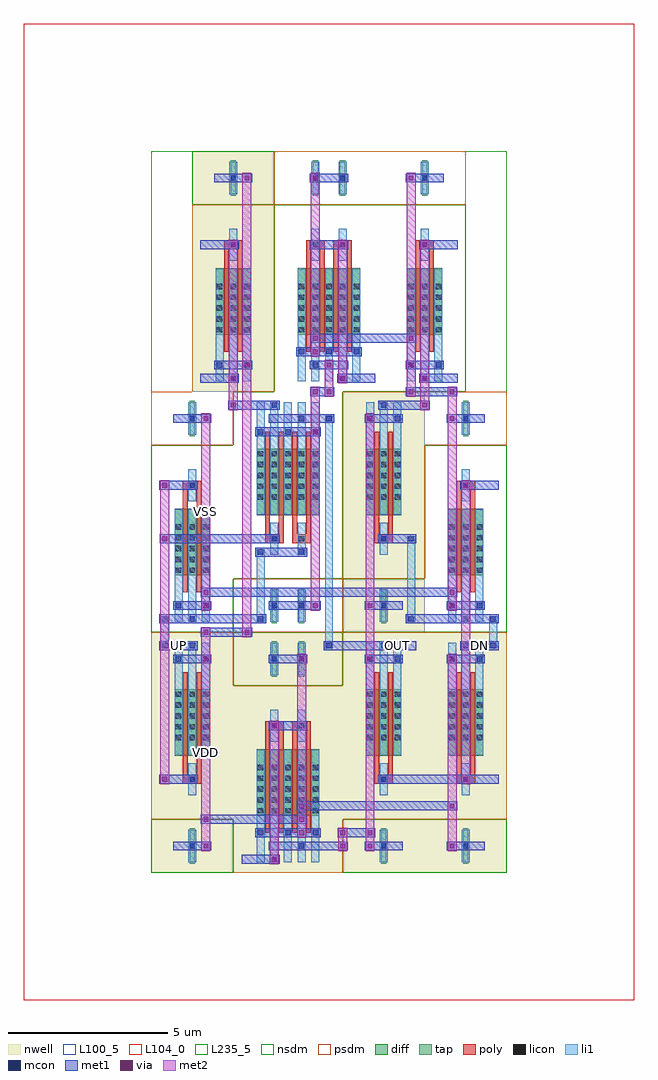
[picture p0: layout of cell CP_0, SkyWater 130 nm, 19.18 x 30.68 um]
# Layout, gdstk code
from math import pi, radians
import gdstk
lib = gdstk.Library(unit=1e-6, precision=1e-09)
def R(c, l, rs):  # rectangles x0, y0, x1, y1
    for r in rs: c.add(gdstk.rectangle(r[:2], r[2:], *l))
def A(c, l, x, y, w, h, nx, ny, dx, dy):  # array of equal rectangles
    R(c, l, [(x+i*dx, y+j*dy, x+i*dx+w, y+j*dy+h) for i in range(nx) for j in range(ny)])
def P(c, l, *ps):  # polygons
    for p in ps: c.add(gdstk.Polygon(p, *l))
nwell = (64, 20)
diff = (65, 20)
tap = (65, 44)
poly = (66, 20)
licon = (66, 44)
li1 = (67, 20)
mcon = (67, 44)
met1 = (68, 20)
via = (68, 44)
met2 = (69, 20)
nsdm = (93, 44)
psdm = (94, 20)
L100_5 = (100, 5)
L104_0 = (104, 0)
L235_5 = (235, 5)

scm_nmos_4295876_x1_y1_1 = lib.new_cell('SCM_NMOS_4295876_X1_Y1_1676481576')
R(scm_nmos_4295876_x1_y1_1, diff, [(0.735,1.785,2.705,3.885)])
R(scm_nmos_4295876_x1_y1_1, tap, [(1.205,6.16,1.375,7.28), (2.065,6.16,2.235,7.28)])
A(scm_nmos_4295876_x1_y1_1, poly, 1, 1.26, 0.15, 3.36, 4, 1, 0.43, 0)
R(scm_nmos_4295876_x1_y1_1, poly, [(1,4.485,1.58,4.755), (1.86,4.485,2.44,4.755)])
A(scm_nmos_4295876_x1_y1_1, licon, 0.775, 1.865, 0.17, 0.17, 3, 5, 0.43, 0.34)
A(scm_nmos_4295876_x1_y1_1, licon, 1.635, 1.865, 0.17, 0.17, 3, 5, 0.43, 0.34)
R(scm_nmos_4295876_x1_y1_1, licon, [(1.205,4.535,1.375,4.705), (2.065,4.535,2.235,4.705), (1.205,6.635,1.375,6.805), (2.065,6.635,2.235,6.805)])
A(scm_nmos_4295876_x1_y1_1, li1, 0.735, 0.335, 0.25, 3.53, 5, 1, 0.43, 0)
R(scm_nmos_4295876_x1_y1_1, li1, [(1.165,4.115,1.415,5.125), (2.025,4.115,2.275,5.125), (1.165,6.215,1.415,7.225), (2.025,6.215,2.275,7.225)])
A(scm_nmos_4295876_x1_y1_1, mcon, 0.775, 1.175, 0.17, 0.17, 3, 1, 0.86, 0)
R(scm_nmos_4295876_x1_y1_1, mcon, [(1.205,0.335,1.375,0.505), (2.065,0.755,2.235,0.925), (1.205,4.535,1.375,4.705), (2.065,4.535,2.235,4.705), (1.205,6.635,1.375,6.805), (2.065,6.635,2.235,6.805)])
R(scm_nmos_4295876_x1_y1_1, met1, [(0.26,0.28,1.46,0.56), (1.12,0.7,2.32,0.98), (0.69,1.12,2.75,1.4), (1.12,4.48,2.32,4.76), (1.12,6.58,2.32,6.86)])
R(scm_nmos_4295876_x1_y1_1, via, [(1.215,0.345,1.365,0.495), (2.075,1.185,2.225,1.335), (1.215,4.545,1.365,4.695), (2.075,6.645,2.225,6.795)])
R(scm_nmos_4295876_x1_y1_1, met2, [(1.15,0.26,1.43,4.78), (2.01,1.1,2.29,6.88)])
R(scm_nmos_4295876_x1_y1_1, nsdm, [(0,0,3.44,5.88)])
R(scm_nmos_4295876_x1_y1_1, psdm, [(0,5.88,3.44,7.56)])
R(scm_nmos_4295876_x1_y1_1, L100_5, [(0,0,3.44,7.56)])

scm_pmos_7694812_x1_y1_1 = lib.new_cell('SCM_PMOS_7694812_X1_Y1_1676481577')
R(scm_pmos_7694812_x1_y1_1, nwell, [(0,0,3.44,7.56)])
R(scm_pmos_7694812_x1_y1_1, diff, [(0.735,1.785,2.705,3.885)])
R(scm_pmos_7694812_x1_y1_1, tap, [(1.205,6.16,1.375,7.28), (2.065,6.16,2.235,7.28)])
A(scm_pmos_7694812_x1_y1_1, poly, 1, 1.26, 0.15, 3.36, 4, 1, 0.43, 0)
R(scm_pmos_7694812_x1_y1_1, poly, [(1,4.485,1.58,4.755), (1.86,4.485,2.44,4.755)])
A(scm_pmos_7694812_x1_y1_1, licon, 0.775, 1.865, 0.17, 0.17, 3, 5, 0.43, 0.34)
A(scm_pmos_7694812_x1_y1_1, licon, 1.635, 1.865, 0.17, 0.17, 3, 5, 0.43, 0.34)
R(scm_pmos_7694812_x1_y1_1, licon, [(1.205,4.535,1.375,4.705), (2.065,4.535,2.235,4.705), (1.205,6.635,1.375,6.805), (2.065,6.635,2.235,6.805)])
A(scm_pmos_7694812_x1_y1_1, li1, 0.735, 0.335, 0.25, 3.53, 5, 1, 0.43, 0)
R(scm_pmos_7694812_x1_y1_1, li1, [(1.165,4.115,1.415,5.125), (2.025,4.115,2.275,5.125), (1.165,6.215,1.415,7.225), (2.025,6.215,2.275,7.225)])
A(scm_pmos_7694812_x1_y1_1, mcon, 0.775, 1.175, 0.17, 0.17, 3, 1, 0.86, 0)
R(scm_pmos_7694812_x1_y1_1, mcon, [(1.205,0.335,1.375,0.505), (2.065,0.755,2.235,0.925), (1.205,4.535,1.375,4.705), (2.065,4.535,2.235,4.705), (1.205,6.635,1.375,6.805), (2.065,6.635,2.235,6.805)])
R(scm_pmos_7694812_x1_y1_1, met1, [(0.26,0.28,1.46,0.56), (1.12,0.7,2.32,0.98), (0.69,1.12,2.75,1.4), (1.12,4.48,2.32,4.76), (1.12,6.58,2.32,6.86)])
R(scm_pmos_7694812_x1_y1_1, via, [(1.215,0.345,1.365,0.495), (2.075,1.185,2.225,1.335), (1.215,4.545,1.365,4.695), (2.075,6.645,2.225,6.795)])
R(scm_pmos_7694812_x1_y1_1, met2, [(1.15,0.26,1.43,4.78), (2.01,1.1,2.29,6.88)])
R(scm_pmos_7694812_x1_y1_1, nsdm, [(0,5.88,3.44,7.56)])
R(scm_pmos_7694812_x1_y1_1, psdm, [(0,0,3.44,5.88)])
R(scm_pmos_7694812_x1_y1_1, L100_5, [(0,0,3.44,7.56)])

nmos_s_72264633_x1_y1_16 = lib.new_cell('NMOS_S_72264633_X1_Y1_1676481568_1676481570')
R(nmos_s_72264633_x1_y1_16, diff, [(0.735,1.785,1.845,3.885)])
R(nmos_s_72264633_x1_y1_16, tap, [(1.205,6.16,1.375,7.28)])
R(nmos_s_72264633_x1_y1_16, poly, [(1,1.26,1.15,4.62), (1.43,1.26,1.58,4.62), (1,4.485,1.58,4.755)])
A(nmos_s_72264633_x1_y1_16, licon, 0.775, 1.865, 0.17, 0.17, 3, 5, 0.43, 0.34)
R(nmos_s_72264633_x1_y1_16, licon, [(1.205,4.535,1.375,4.705), (1.205,6.635,1.375,6.805)])
A(nmos_s_72264633_x1_y1_16, li1, 0.735, 0.335, 0.25, 3.53, 3, 1, 0.43, 0)
R(nmos_s_72264633_x1_y1_16, li1, [(1.165,4.115,1.415,5.125), (1.165,6.215,1.415,7.225)])
R(nmos_s_72264633_x1_y1_16, mcon, [(1.205,0.335,1.375,0.505), (0.775,0.755,0.945,0.925), (1.635,0.755,1.805,0.925), (1.205,4.535,1.375,4.705), (1.205,6.635,1.375,6.805)])
R(nmos_s_72264633_x1_y1_16, met1, [(0.26,0.28,1.46,0.56), (0.69,0.7,1.89,0.98), (0.26,4.48,1.46,4.76), (0.69,6.58,1.89,6.86)])
R(nmos_s_72264633_x1_y1_16, via, [(1.645,0.765,1.795,0.915), (1.645,6.645,1.795,6.795)])
R(nmos_s_72264633_x1_y1_16, met2, [(1.58,0.68,1.86,6.88)])
R(nmos_s_72264633_x1_y1_16, nsdm, [(0,0,2.58,5.88)])
R(nmos_s_72264633_x1_y1_16, psdm, [(0,5.88,2.58,7.56)])
R(nmos_s_72264633_x1_y1_16, L100_5, [(0,0,2.58,7.56)])

pmos_s_19745913_x1_y1_16 = lib.new_cell('PMOS_S_19745913_X1_Y1_1676481569_1676481570')
R(pmos_s_19745913_x1_y1_16, nwell, [(0,0,2.58,7.56)])
R(pmos_s_19745913_x1_y1_16, diff, [(0.735,1.785,1.845,3.885)])
R(pmos_s_19745913_x1_y1_16, tap, [(1.205,6.16,1.375,7.28)])
R(pmos_s_19745913_x1_y1_16, poly, [(1,1.26,1.15,4.62), (1.43,1.26,1.58,4.62), (1,4.485,1.58,4.755)])
A(pmos_s_19745913_x1_y1_16, licon, 0.775, 1.865, 0.17, 0.17, 3, 5, 0.43, 0.34)
R(pmos_s_19745913_x1_y1_16, licon, [(1.205,4.535,1.375,4.705), (1.205,6.635,1.375,6.805)])
A(pmos_s_19745913_x1_y1_16, li1, 0.735, 0.335, 0.25, 3.53, 3, 1, 0.43, 0)
R(pmos_s_19745913_x1_y1_16, li1, [(1.165,4.115,1.415,5.125), (1.165,6.215,1.415,7.225)])
R(pmos_s_19745913_x1_y1_16, mcon, [(1.205,0.335,1.375,0.505), (0.775,0.755,0.945,0.925), (1.635,0.755,1.805,0.925), (1.205,4.535,1.375,4.705), (1.205,6.635,1.375,6.805)])
R(pmos_s_19745913_x1_y1_16, met1, [(0.26,0.28,1.46,0.56), (0.69,0.7,1.89,0.98), (0.26,4.48,1.46,4.76), (0.69,6.58,1.89,6.86)])
R(pmos_s_19745913_x1_y1_16, via, [(1.645,0.765,1.795,0.915), (1.645,6.645,1.795,6.795)])
R(pmos_s_19745913_x1_y1_16, met2, [(1.58,0.68,1.86,6.88)])
R(pmos_s_19745913_x1_y1_16, nsdm, [(0,5.88,2.58,7.56)])
R(pmos_s_19745913_x1_y1_16, psdm, [(0,0,2.58,5.88)])
R(pmos_s_19745913_x1_y1_16, L100_5, [(0,0,2.58,7.56)])

inv_1445845_0_0_16764815 = lib.new_cell('INV_1445845_0_0_1676481570')
R(inv_1445845_0_0_16764815, li1, [(2.025,7.055,2.275,7.225), (2.025,7.055,2.275,7.225), (2.025,7.14,2.275,7.98), (2.025,7.895,2.275,8.065), (2.025,7.895,2.275,8.065)])
R(inv_1445845_0_0_16764815, mcon, [(2.065,7.055,2.235,7.225), (2.065,7.055,2.235,7.225), (2.065,7.895,2.235,8.065), (2.065,7.895,2.235,8.065)])
R(inv_1445845_0_0_16764815, met1, [(1.99,2.8,2.31,3.08), (1.99,2.8,2.31,3.08), (1.98,7,2.32,7.28), (1.98,7,2.32,7.28), (1.98,7.84,2.32,8.12), (1.98,7.84,2.32,8.12), (1.99,12.04,2.31,12.32), (1.99,12.04,2.31,12.32)])
P(inv_1445845_0_0_16764815, met1, [(0,0),(0,0),(0,0),(0,0)],
  [(0,0),(0,0),(0,0),(0,0)],
  [(0,0),(0,0),(0,0),(0,0)],
  [(0,0),(0,0),(0,0),(0,0)])
R(inv_1445845_0_0_16764815, via, [(2.075,2.865,2.225,3.015), (2.075,2.865,2.225,3.015), (2.075,12.105,2.225,12.255), (2.075,12.105,2.225,12.255)])
R(inv_1445845_0_0_16764815, met2, [(2.01,2.78,2.29,3.1), (2.01,2.78,2.29,3.1), (2.01,2.94,2.29,12.18), (2.01,12.02,2.29,12.34), (2.01,12.02,2.29,12.34)])
P(inv_1445845_0_0_16764815, met2, [(0,0),(0,0),(0,0),(0,0)],
  [(0,0),(0,0),(0,0),(0,0)])
R(inv_1445845_0_0_16764815, L235_5, [(0,0,2.58,15.12)])
inv_1445845_0_0_16764815.add(gdstk.Reference(nmos_s_72264633_x1_y1_16, (2.58,7.56), rotation=pi))
inv_1445845_0_0_16764815.add(gdstk.Reference(pmos_s_19745913_x1_y1_16, (2.58,7.56), rotation=pi, x_reflection=True))

c_nmos_s_72264633_x1_y1_16 = lib.new_cell('NMOS_S_72264633_X1_Y1_1676481568_1676481571')
R(c_nmos_s_72264633_x1_y1_16, diff, [(0.735,1.785,1.845,3.885)])
R(c_nmos_s_72264633_x1_y1_16, tap, [(1.205,6.16,1.375,7.28)])
R(c_nmos_s_72264633_x1_y1_16, poly, [(1,1.26,1.15,4.62), (1.43,1.26,1.58,4.62), (1,4.485,1.58,4.755)])
A(c_nmos_s_72264633_x1_y1_16, licon, 0.775, 1.865, 0.17, 0.17, 3, 5, 0.43, 0.34)
R(c_nmos_s_72264633_x1_y1_16, licon, [(1.205,4.535,1.375,4.705), (1.205,6.635,1.375,6.805)])
A(c_nmos_s_72264633_x1_y1_16, li1, 0.735, 0.335, 0.25, 3.53, 3, 1, 0.43, 0)
R(c_nmos_s_72264633_x1_y1_16, li1, [(1.165,4.115,1.415,5.125), (1.165,6.215,1.415,7.225)])
R(c_nmos_s_72264633_x1_y1_16, mcon, [(1.205,0.335,1.375,0.505), (0.775,0.755,0.945,0.925), (1.635,0.755,1.805,0.925), (1.205,4.535,1.375,4.705), (1.205,6.635,1.375,6.805)])
R(c_nmos_s_72264633_x1_y1_16, met1, [(0.26,0.28,1.46,0.56), (0.69,0.7,1.89,0.98), (0.26,4.48,1.46,4.76), (0.69,6.58,1.89,6.86)])
R(c_nmos_s_72264633_x1_y1_16, via, [(1.645,0.765,1.795,0.915), (1.645,6.645,1.795,6.795)])
R(c_nmos_s_72264633_x1_y1_16, met2, [(1.58,0.68,1.86,6.88)])
R(c_nmos_s_72264633_x1_y1_16, nsdm, [(0,0,2.58,5.88)])
R(c_nmos_s_72264633_x1_y1_16, psdm, [(0,5.88,2.58,7.56)])
R(c_nmos_s_72264633_x1_y1_16, L100_5, [(0,0,2.58,7.56)])

c_pmos_s_19745913_x1_y1_16 = lib.new_cell('PMOS_S_19745913_X1_Y1_1676481569_1676481571')
R(c_pmos_s_19745913_x1_y1_16, nwell, [(0,0,2.58,7.56)])
R(c_pmos_s_19745913_x1_y1_16, diff, [(0.735,1.785,1.845,3.885)])
R(c_pmos_s_19745913_x1_y1_16, tap, [(1.205,6.16,1.375,7.28)])
R(c_pmos_s_19745913_x1_y1_16, poly, [(1,1.26,1.15,4.62), (1.43,1.26,1.58,4.62), (1,4.485,1.58,4.755)])
A(c_pmos_s_19745913_x1_y1_16, licon, 0.775, 1.865, 0.17, 0.17, 3, 5, 0.43, 0.34)
R(c_pmos_s_19745913_x1_y1_16, licon, [(1.205,4.535,1.375,4.705), (1.205,6.635,1.375,6.805)])
A(c_pmos_s_19745913_x1_y1_16, li1, 0.735, 0.335, 0.25, 3.53, 3, 1, 0.43, 0)
R(c_pmos_s_19745913_x1_y1_16, li1, [(1.165,4.115,1.415,5.125), (1.165,6.215,1.415,7.225)])
R(c_pmos_s_19745913_x1_y1_16, mcon, [(1.205,0.335,1.375,0.505), (0.775,0.755,0.945,0.925), (1.635,0.755,1.805,0.925), (1.205,4.535,1.375,4.705), (1.205,6.635,1.375,6.805)])
R(c_pmos_s_19745913_x1_y1_16, met1, [(0.26,0.28,1.46,0.56), (0.69,0.7,1.89,0.98), (0.26,4.48,1.46,4.76), (0.69,6.58,1.89,6.86)])
R(c_pmos_s_19745913_x1_y1_16, via, [(1.645,0.765,1.795,0.915), (1.645,6.645,1.795,6.795)])
R(c_pmos_s_19745913_x1_y1_16, met2, [(1.58,0.68,1.86,6.88)])
R(c_pmos_s_19745913_x1_y1_16, nsdm, [(0,5.88,2.58,7.56)])
R(c_pmos_s_19745913_x1_y1_16, psdm, [(0,0,2.58,5.88)])
R(c_pmos_s_19745913_x1_y1_16, L100_5, [(0,0,2.58,7.56)])

inv_1445845_1_0_16764815 = lib.new_cell('INV_1445845_1_0_1676481571')
R(inv_1445845_1_0_16764815, li1, [(2.025,7.055,2.275,7.225), (2.025,7.055,2.275,7.225), (2.025,7.14,2.275,7.98), (2.025,7.895,2.275,8.065), (2.025,7.895,2.275,8.065)])
R(inv_1445845_1_0_16764815, mcon, [(2.065,7.055,2.235,7.225), (2.065,7.055,2.235,7.225), (2.065,7.895,2.235,8.065), (2.065,7.895,2.235,8.065)])
R(inv_1445845_1_0_16764815, met1, [(1.13,2.8,1.45,3.08), (1.13,2.8,1.45,3.08), (1.98,7,2.32,7.28), (1.98,7,2.32,7.28), (1.98,7.84,2.32,8.12), (1.98,7.84,2.32,8.12), (1.13,12.04,1.45,12.32), (1.13,12.04,1.45,12.32)])
P(inv_1445845_1_0_16764815, met1, [(0,0),(0,0),(0,0),(0,0)],
  [(0,0),(0,0),(0,0),(0,0)],
  [(0,0),(0,0),(0,0),(0,0)],
  [(0,0),(0,0),(0,0),(0,0)])
R(inv_1445845_1_0_16764815, via, [(1.215,2.865,1.365,3.015), (1.215,2.865,1.365,3.015), (1.215,12.105,1.365,12.255), (1.215,12.105,1.365,12.255)])
R(inv_1445845_1_0_16764815, met2, [(1.15,2.78,1.43,3.1), (1.15,2.78,1.43,3.1), (1.15,2.94,1.43,12.18), (1.15,12.02,1.43,12.34), (1.15,12.02,1.43,12.34)])
P(inv_1445845_1_0_16764815, met2, [(0,0),(0,0),(0,0),(0,0)],
  [(0,0),(0,0),(0,0),(0,0)])
R(inv_1445845_1_0_16764815, L235_5, [(0,0,2.58,15.12)])
inv_1445845_1_0_16764815.add(gdstk.Reference(c_nmos_s_72264633_x1_y1_16, (2.58,7.56), rotation=pi))
inv_1445845_1_0_16764815.add(gdstk.Reference(c_pmos_s_19745913_x1_y1_16, (2.58,7.56), rotation=pi, x_reflection=True))

dp_nmos_87919044_x1_y1_1 = lib.new_cell('DP_NMOS_87919044_X1_Y1_1676481574')
R(dp_nmos_87919044_x1_y1_1, diff, [(0.735,1.785,2.705,3.885)])
R(dp_nmos_87919044_x1_y1_1, tap, [(1.205,6.16,1.375,7.28), (2.065,6.16,2.235,7.28)])
A(dp_nmos_87919044_x1_y1_1, poly, 1, 1.26, 0.15, 3.36, 4, 1, 0.43, 0)
R(dp_nmos_87919044_x1_y1_1, poly, [(1,4.485,1.58,4.755), (1.86,4.485,2.44,4.755)])
A(dp_nmos_87919044_x1_y1_1, licon, 0.775, 1.865, 0.17, 0.17, 3, 5, 0.43, 0.34)
A(dp_nmos_87919044_x1_y1_1, licon, 1.635, 1.865, 0.17, 0.17, 3, 5, 0.43, 0.34)
R(dp_nmos_87919044_x1_y1_1, licon, [(1.205,4.535,1.375,4.705), (2.065,4.535,2.235,4.705), (1.205,6.635,1.375,6.805), (2.065,6.635,2.235,6.805)])
A(dp_nmos_87919044_x1_y1_1, li1, 0.735, 0.335, 0.25, 3.53, 5, 1, 0.43, 0)
R(dp_nmos_87919044_x1_y1_1, li1, [(1.165,4.115,1.415,5.125), (2.025,4.115,2.275,5.125), (1.165,6.215,1.415,7.225), (2.025,6.215,2.275,7.225)])
A(dp_nmos_87919044_x1_y1_1, mcon, 0.775, 1.175, 0.17, 0.17, 3, 1, 0.86, 0)
R(dp_nmos_87919044_x1_y1_1, mcon, [(1.205,0.335,1.375,0.505), (2.065,0.755,2.235,0.925), (1.205,4.535,1.375,4.705), (2.065,4.955,2.235,5.125), (1.205,6.635,1.375,6.805), (2.065,6.635,2.235,6.805)])
R(dp_nmos_87919044_x1_y1_1, met1, [(0.26,0.28,1.46,0.56), (1.12,0.7,2.32,0.98), (0.69,1.12,2.75,1.4), (0.26,4.48,1.46,4.76), (1.12,4.9,2.32,5.18), (1.12,6.58,2.75,6.86)])
R(dp_nmos_87919044_x1_y1_1, via, [(2.505,1.185,2.655,1.335), (2.505,6.645,2.655,6.795)])
R(dp_nmos_87919044_x1_y1_1, met2, [(2.44,1.1,2.72,6.88)])
R(dp_nmos_87919044_x1_y1_1, nsdm, [(0,0,3.44,5.88)])
R(dp_nmos_87919044_x1_y1_1, psdm, [(0,5.88,3.44,7.56)])
R(dp_nmos_87919044_x1_y1_1, L100_5, [(0,0,3.44,7.56)])

dcl_nmos_s_53290777_x1_y = lib.new_cell('DCL_NMOS_S_53290777_X1_Y1_1676481572')
R(dcl_nmos_s_53290777_x1_y, diff, [(0.735,1.785,1.845,3.885)])
R(dcl_nmos_s_53290777_x1_y, tap, [(1.205,6.16,1.375,7.28)])
R(dcl_nmos_s_53290777_x1_y, poly, [(1,1.26,1.15,4.62), (1.43,1.26,1.58,4.62), (1,4.485,1.58,4.755)])
A(dcl_nmos_s_53290777_x1_y, licon, 0.775, 1.865, 0.17, 0.17, 3, 5, 0.43, 0.34)
R(dcl_nmos_s_53290777_x1_y, licon, [(1.205,4.535,1.375,4.705), (1.205,6.635,1.375,6.805)])
A(dcl_nmos_s_53290777_x1_y, li1, 0.735, 0.335, 0.25, 3.53, 3, 1, 0.43, 0)
R(dcl_nmos_s_53290777_x1_y, li1, [(1.165,4.115,1.415,5.125), (1.165,6.215,1.415,7.225)])
R(dcl_nmos_s_53290777_x1_y, mcon, [(1.205,0.335,1.375,0.505), (0.775,0.755,0.945,0.925), (1.635,0.755,1.805,0.925), (1.205,4.535,1.375,4.705), (1.205,6.635,1.375,6.805)])
R(dcl_nmos_s_53290777_x1_y, met1, [(0.26,0.28,1.46,0.56), (0.69,0.7,1.89,0.98), (0.26,4.48,1.46,4.76), (0.69,6.58,1.89,6.86)])
R(dcl_nmos_s_53290777_x1_y, via, [(1.215,0.345,1.365,0.495), (1.645,0.765,1.795,0.915), (1.215,4.545,1.365,4.695), (1.645,6.645,1.795,6.795)])
R(dcl_nmos_s_53290777_x1_y, met2, [(1.15,0.26,1.43,4.78), (1.58,0.68,1.86,6.88)])
R(dcl_nmos_s_53290777_x1_y, nsdm, [(0,0,2.58,5.88)])
R(dcl_nmos_s_53290777_x1_y, psdm, [(0,5.88,2.58,7.56)])
R(dcl_nmos_s_53290777_x1_y, L100_5, [(0,0,2.58,7.56)])

dcl_pmos_s_72600235_x1_y = lib.new_cell('DCL_PMOS_S_72600235_X1_Y1_1676481573')
R(dcl_pmos_s_72600235_x1_y, nwell, [(0,0,2.58,7.56)])
R(dcl_pmos_s_72600235_x1_y, diff, [(0.735,1.785,1.845,3.885)])
R(dcl_pmos_s_72600235_x1_y, tap, [(1.205,6.16,1.375,7.28)])
R(dcl_pmos_s_72600235_x1_y, poly, [(1,1.26,1.15,4.62), (1.43,1.26,1.58,4.62), (1,4.485,1.58,4.755)])
A(dcl_pmos_s_72600235_x1_y, licon, 0.775, 1.865, 0.17, 0.17, 3, 5, 0.43, 0.34)
R(dcl_pmos_s_72600235_x1_y, licon, [(1.205,4.535,1.375,4.705), (1.205,6.635,1.375,6.805)])
A(dcl_pmos_s_72600235_x1_y, li1, 0.735, 0.335, 0.25, 3.53, 3, 1, 0.43, 0)
R(dcl_pmos_s_72600235_x1_y, li1, [(1.165,4.115,1.415,5.125), (1.165,6.215,1.415,7.225)])
R(dcl_pmos_s_72600235_x1_y, mcon, [(1.205,0.335,1.375,0.505), (0.775,0.755,0.945,0.925), (1.635,0.755,1.805,0.925), (1.205,4.535,1.375,4.705), (1.205,6.635,1.375,6.805)])
R(dcl_pmos_s_72600235_x1_y, met1, [(0.26,0.28,1.46,0.56), (0.69,0.7,1.89,0.98), (0.26,4.48,1.46,4.76), (0.69,6.58,1.89,6.86)])
R(dcl_pmos_s_72600235_x1_y, via, [(1.215,0.345,1.365,0.495), (1.645,0.765,1.795,0.915), (1.215,4.545,1.365,4.695), (1.645,6.645,1.795,6.795)])
R(dcl_pmos_s_72600235_x1_y, met2, [(1.15,0.26,1.43,4.78), (1.58,0.68,1.86,6.88)])
R(dcl_pmos_s_72600235_x1_y, nsdm, [(0,5.88,2.58,7.56)])
R(dcl_pmos_s_72600235_x1_y, psdm, [(0,0,2.58,5.88)])
R(dcl_pmos_s_72600235_x1_y, L100_5, [(0,0,2.58,7.56)])

c_pmos_s_19745913_x1_y1_16_ = lib.new_cell('PMOS_S_19745913_X1_Y1_1676481575')
R(c_pmos_s_19745913_x1_y1_16_, nwell, [(0,0,2.58,7.56)])
R(c_pmos_s_19745913_x1_y1_16_, diff, [(0.735,1.785,1.845,3.885)])
R(c_pmos_s_19745913_x1_y1_16_, tap, [(1.205,6.16,1.375,7.28)])
R(c_pmos_s_19745913_x1_y1_16_, poly, [(1,1.26,1.15,4.62), (1.43,1.26,1.58,4.62), (1,4.485,1.58,4.755)])
A(c_pmos_s_19745913_x1_y1_16_, licon, 0.775, 1.865, 0.17, 0.17, 3, 5, 0.43, 0.34)
R(c_pmos_s_19745913_x1_y1_16_, licon, [(1.205,4.535,1.375,4.705), (1.205,6.635,1.375,6.805)])
A(c_pmos_s_19745913_x1_y1_16_, li1, 0.735, 0.335, 0.25, 3.53, 3, 1, 0.43, 0)
R(c_pmos_s_19745913_x1_y1_16_, li1, [(1.165,4.115,1.415,5.125), (1.165,6.215,1.415,7.225)])
R(c_pmos_s_19745913_x1_y1_16_, mcon, [(1.205,0.335,1.375,0.505), (0.775,0.755,0.945,0.925), (1.635,0.755,1.805,0.925), (1.205,4.535,1.375,4.705), (1.205,6.635,1.375,6.805)])
R(c_pmos_s_19745913_x1_y1_16_, met1, [(0.26,0.28,1.46,0.56), (0.69,0.7,1.89,0.98), (0.26,4.48,1.46,4.76), (0.69,6.58,1.89,6.86)])
R(c_pmos_s_19745913_x1_y1_16_, via, [(1.645,0.765,1.795,0.915), (1.645,6.645,1.795,6.795)])
R(c_pmos_s_19745913_x1_y1_16_, met2, [(1.58,0.68,1.86,6.88)])
R(c_pmos_s_19745913_x1_y1_16_, nsdm, [(0,5.88,2.58,7.56)])
R(c_pmos_s_19745913_x1_y1_16_, psdm, [(0,0,2.58,5.88)])
R(c_pmos_s_19745913_x1_y1_16_, L100_5, [(0,0,2.58,7.56)])

cp_0 = lib.new_cell('CP_0')
R(cp_0, li1, [(5.465,7.055,5.715,7.225), (5.465,7.055,5.715,7.225), (5.465,7.14,5.715,14.28), (3.315,7.895,3.565,8.065), (3.315,7.895,3.565,8.065), (8.045,7.895,8.295,8.065), (8.045,7.895,8.295,8.065), (3.315,7.98,3.565,10.08), (8.045,7.98,8.295,10.5), (3.315,9.995,3.565,10.165), (3.315,9.995,3.565,10.165), (8.045,10.415,8.295,10.585), (8.045,10.415,8.295,10.585), (5.465,14.195,5.715,14.365), (5.465,14.195,5.715,14.365)])
P(cp_0, li1, [(0,0),(0,0),(0,0),(0,0)],
  [(0,0),(0,0),(0,0),(0,0)])
R(cp_0, mcon, [(5.505,7.055,5.675,7.225), (5.505,7.055,5.675,7.225), (3.355,7.895,3.525,8.065), (3.355,7.895,3.525,8.065), (8.085,7.895,8.255,8.065), (8.085,7.895,8.255,8.065), (3.355,9.995,3.525,10.165), (3.355,9.995,3.525,10.165), (8.085,10.415,8.255,10.585), (8.085,10.415,8.255,10.585), (5.505,14.195,5.675,14.365), (5.505,14.195,5.675,14.365)])
R(cp_0, met1, [(4.73,0.7,6.02,0.98), (5.86,0.7,6.18,0.98), (5.86,0.7,6.18,0.98), (5.86,0.7,6.18,0.98), (5.86,0.7,6.18,0.98), (5.86,1.12,6.18,1.4), (5.86,1.12,6.18,1.4), (5.86,1.12,6.18,1.4), (5.86,1.12,6.18,1.4), (6.02,1.12,6.88,1.4), (6.72,1.12,7.04,1.4), (6.72,1.12,7.04,1.4), (6.72,1.12,7.04,1.4), (6.72,1.12,7.04,1.4), (1.56,1.54,1.88,1.82), (1.56,1.54,1.88,1.82), (1.56,1.54,1.88,1.82), (1.56,1.54,1.88,1.82), (1.56,1.54,1.88,1.82), (1.56,1.54,1.88,1.82), (1.72,1.54,4.73,1.82), (4.57,1.54,4.89,1.82), (4.57,1.54,4.89,1.82), (4.57,1.54,4.89,1.82), (4.57,1.54,4.89,1.82), (4.57,1.54,4.89,1.82), (4.57,1.54,4.89,1.82), (4.57,1.96,4.89,2.24), (4.57,1.96,4.89,2.24), (4.57,1.96,4.89,2.24), (4.57,1.96,4.89,2.24), (4.73,1.96,9.46,2.24), (9.3,1.96,9.62,2.24), (9.3,1.96,9.62,2.24), (9.3,1.96,9.62,2.24), (9.3,1.96,9.62,2.24), (8.17,2.8,9.89,3.08), (5.42,7,5.76,7.28), (5.42,7,5.76,7.28), (5.59,7,7.31,7.28), (1.56,7.42,1.88,7.7), (1.56,7.42,1.88,7.7), (1.72,7.42,3.01,7.7), (2.85,7.42,3.17,7.7), (2.85,7.42,3.17,7.7), (1.29,7.84,3.44,8.12), (3.27,7.84,3.61,8.12), (3.27,7.84,3.61,8.12), (8,7.84,8.34,8.12), (8,7.84,8.34,8.12), (8.17,7.84,9.89,8.12), (1.56,8.68,1.88,8.96), (1.56,8.68,1.88,8.96), (1.56,8.68,1.88,8.96), (1.56,8.68,1.88,8.96), (1.56,8.68,1.88,8.96), (1.56,8.68,1.88,8.96), (1.72,8.68,9.46,8.96), (9.3,8.68,9.62,8.96), (9.3,8.68,9.62,8.96), (9.3,8.68,9.62,8.96), (9.3,8.68,9.62,8.96), (9.3,8.68,9.62,8.96), (9.3,8.68,9.62,8.96), (3.27,9.94,3.61,10.22), (3.27,9.94,3.61,10.22), (3.44,9.94,3.87,10.22), (0.27,10.36,0.59,10.64), (0.27,10.36,0.59,10.64), (0.43,10.36,3.01,10.64), (8,10.36,8.34,10.64), (8,10.36,8.34,10.64), (4.73,14.14,5.59,14.42), (5.42,14.14,5.76,14.42), (5.42,14.14,5.76,14.42), (2.42,14.56,2.74,14.84), (2.42,14.56,2.74,14.84), (2.58,14.56,3.01,14.84), (8.17,14.56,8.6,14.84), (8.44,14.56,8.76,14.84), (8.44,14.56,8.76,14.84), (5,14.98,5.32,15.26), (5,14.98,5.32,15.26), (5.16,14.98,5.59,15.26), (5.43,14.98,5.75,15.26), (5.43,14.98,5.75,15.26), (8.01,14.98,8.33,15.26), (8.01,14.98,8.33,15.26), (8.01,14.98,8.33,15.26), (8.01,14.98,8.33,15.26), (8.17,14.98,9.46,15.26), (9.3,14.98,9.62,15.26), (9.3,14.98,9.62,15.26), (9.3,14.98,9.62,15.26), (9.3,14.98,9.62,15.26), (5.43,15.82,5.75,16.1), (5.43,15.82,5.75,16.1), (5,16.66,5.32,16.94), (5,16.66,5.32,16.94), (5.16,16.66,8.17,16.94), (8.01,16.66,8.33,16.94), (8.01,16.66,8.33,16.94)])
P(cp_0, met1, [(0,0),(0,0),(0,0),(0,0)],
  [(0,0),(0,0),(0,0),(0,0)],
  [(0,0),(0,0),(0,0),(0,0)],
  [(0,0),(0,0),(0,0),(0,0)],
  [(0,0),(0,0),(0,0),(0,0)],
  [(0,0),(0,0),(0,0),(0,0)],
  [(0,0),(0,0),(0,0),(0,0)],
  [(0,0),(0,0),(0,0),(0,0)],
  [(0,0),(0,0),(0,0),(0,0)],
  [(0,0),(0,0),(0,0),(0,0)],
  [(0,0),(0,0),(0,0),(0,0)],
  [(0,0),(0,0),(0,0),(0,0)],
  [(0,0),(0,0),(0,0),(0,0)],
  [(0,0),(0,0),(0,0),(0,0)],
  [(0,0),(0,0),(0,0),(0,0)],
  [(0,0),(0,0),(0,0),(0,0)],
  [(0,0),(0,0),(0,0),(0,0)],
  [(0,0),(0,0),(0,0),(0,0)],
  [(0,0),(0,0),(0,0),(0,0)],
  [(0,0),(0,0),(0,0),(0,0)],
  [(0,0),(0,0),(0,0),(0,0)],
  [(0,0),(0,0),(0,0),(0,0)],
  [(0,0),(0,0),(0,0),(0,0)],
  [(0,0),(0,0),(0,0),(0,0)],
  [(0,0),(0,0),(0,0),(0,0)],
  [(0,0),(0,0),(0,0),(0,0)],
  [(0,0),(0,0),(0,0),(0,0)],
  [(0,0),(0,0),(0,0),(0,0)],
  [(0,0),(0,0),(0,0),(0,0)])
R(cp_0, via, [(5.945,0.765,6.095,0.915), (5.945,0.765,6.095,0.915), (5.945,0.765,6.095,0.915), (5.945,0.765,6.095,0.915), (5.945,1.185,6.095,1.335), (5.945,1.185,6.095,1.335), (5.945,1.185,6.095,1.335), (5.945,1.185,6.095,1.335), (6.805,1.185,6.955,1.335), (6.805,1.185,6.955,1.335), (6.805,1.185,6.955,1.335), (6.805,1.185,6.955,1.335), (1.645,1.605,1.795,1.755), (1.645,1.605,1.795,1.755), (1.645,1.605,1.795,1.755), (1.645,1.605,1.795,1.755), (1.645,1.605,1.795,1.755), (1.645,1.605,1.795,1.755), (4.655,1.605,4.805,1.755), (4.655,1.605,4.805,1.755), (4.655,1.605,4.805,1.755), (4.655,1.605,4.805,1.755), (4.655,1.605,4.805,1.755), (4.655,1.605,4.805,1.755), (4.655,2.025,4.805,2.175), (4.655,2.025,4.805,2.175), (4.655,2.025,4.805,2.175), (4.655,2.025,4.805,2.175), (9.385,2.025,9.535,2.175), (9.385,2.025,9.535,2.175), (9.385,2.025,9.535,2.175), (9.385,2.025,9.535,2.175), (1.645,7.485,1.795,7.635), (1.645,7.485,1.795,7.635), (2.935,7.485,3.085,7.635), (2.935,7.485,3.085,7.635), (1.645,8.745,1.795,8.895), (1.645,8.745,1.795,8.895), (1.645,8.745,1.795,8.895), (1.645,8.745,1.795,8.895), (1.645,8.745,1.795,8.895), (1.645,8.745,1.795,8.895), (9.385,8.745,9.535,8.895), (9.385,8.745,9.535,8.895), (9.385,8.745,9.535,8.895), (9.385,8.745,9.535,8.895), (9.385,8.745,9.535,8.895), (9.385,8.745,9.535,8.895), (0.355,10.425,0.505,10.575), (0.355,10.425,0.505,10.575), (2.505,14.625,2.655,14.775), (2.505,14.625,2.655,14.775), (8.525,14.625,8.675,14.775), (8.525,14.625,8.675,14.775), (5.085,15.045,5.235,15.195), (5.085,15.045,5.235,15.195), (5.515,15.045,5.665,15.195), (5.515,15.045,5.665,15.195), (8.095,15.045,8.245,15.195), (8.095,15.045,8.245,15.195), (8.095,15.045,8.245,15.195), (8.095,15.045,8.245,15.195), (9.385,15.045,9.535,15.195), (9.385,15.045,9.535,15.195), (9.385,15.045,9.535,15.195), (9.385,15.045,9.535,15.195), (5.515,15.885,5.665,16.035), (5.515,15.885,5.665,16.035), (5.085,16.725,5.235,16.875), (5.085,16.725,5.235,16.875), (8.095,16.725,8.245,16.875), (8.095,16.725,8.245,16.875)])
R(cp_0, met2, [(5.88,0.68,6.16,1), (5.88,0.68,6.16,1), (5.88,0.68,6.16,1), (5.88,0.68,6.16,1), (5.88,0.84,6.16,1.26), (5.88,1.1,6.16,1.42), (5.88,1.1,6.16,1.42), (5.88,1.1,6.16,1.42), (5.88,1.1,6.16,1.42), (6.74,1.1,7.02,1.42), (6.74,1.1,7.02,1.42), (6.74,1.1,7.02,1.42), (6.74,1.1,7.02,1.42), (1.58,1.52,1.86,1.84), (1.58,1.52,1.86,1.84), (1.58,1.52,1.86,1.84), (1.58,1.52,1.86,1.84), (1.58,1.52,1.86,1.84), (1.58,1.52,1.86,1.84), (4.59,1.52,4.87,1.84), (4.59,1.52,4.87,1.84), (4.59,1.52,4.87,1.84), (4.59,1.52,4.87,1.84), (4.59,1.52,4.87,1.84), (4.59,1.52,4.87,1.84), (4.59,1.94,4.87,2.26), (4.59,1.94,4.87,2.26), (4.59,1.94,4.87,2.26), (4.59,1.94,4.87,2.26), (9.32,1.94,9.6,2.26), (9.32,1.94,9.6,2.26), (9.32,1.94,9.6,2.26), (9.32,1.94,9.6,2.26), (1.58,6.72,1.86,7.56), (6.74,6.72,7.02,8.4), (1.58,7.4,1.86,7.72), (1.58,7.4,1.86,7.72), (2.87,7.4,3.15,7.72), (2.87,7.4,3.15,7.72), (2.87,7.56,3.15,15.96), (1.58,8.66,1.86,8.98), (1.58,8.66,1.86,8.98), (1.58,8.66,1.86,8.98), (1.58,8.66,1.86,8.98), (1.58,8.66,1.86,8.98), (1.58,8.66,1.86,8.98), (9.32,8.66,9.6,8.98), (9.32,8.66,9.6,8.98), (9.32,8.66,9.6,8.98), (9.32,8.66,9.6,8.98), (9.32,8.66,9.6,8.98), (9.32,8.66,9.6,8.98), (0.29,10.34,0.57,10.66), (0.29,10.34,0.57,10.66), (5.02,13.86,5.3,15.12), (9.32,14.28,9.6,15.12), (2.44,14.54,2.72,14.86), (2.44,14.54,2.72,14.86), (8.46,14.54,8.74,14.86), (8.46,14.54,8.74,14.86), (2.44,14.7,2.72,15.54), (8.46,14.7,8.74,15.54), (5.02,14.96,5.3,15.28), (5.02,14.96,5.3,15.28), (5.45,14.96,5.73,15.28), (5.45,14.96,5.73,15.28), (8.03,14.96,8.31,15.28), (8.03,14.96,8.31,15.28), (8.03,14.96,8.31,15.28), (8.03,14.96,8.31,15.28), (9.32,14.96,9.6,15.28), (9.32,14.96,9.6,15.28), (9.32,14.96,9.6,15.28), (9.32,14.96,9.6,15.28), (5.45,15.12,5.73,15.96), (8.03,15.12,8.31,15.96), (5.45,15.8,5.73,16.12), (5.45,15.8,5.73,16.12), (5.02,16.64,5.3,16.96), (5.02,16.64,5.3,16.96), (8.03,16.64,8.31,16.96), (8.03,16.64,8.31,16.96)])
P(cp_0, met2, [(0,0),(0,0),(0,0),(0,0)],
  [(0,0),(0,0),(0,0),(0,0)],
  [(0,0),(0,0),(0,0),(0,0)],
  [(0,0),(0,0),(0,0),(0,0)],
  [(0,0),(0,0),(0,0),(0,0)],
  [(0,0),(0,0),(0,0),(0,0)],
  [(0,0),(0,0),(0,0),(0,0)],
  [(0,0),(0,0),(0,0),(0,0)],
  [(0,0),(0,0),(0,0),(0,0)],
  [(0,0),(0,0),(0,0),(0,0)],
  [(0,0),(0,0),(0,0),(0,0)],
  [(0,0),(0,0),(0,0),(0,0)],
  [(0,0),(0,0),(0,0),(0,0)],
  [(0,0),(0,0),(0,0),(0,0)],
  [(0,0),(0,0),(0,0),(0,0)],
  [(0,0),(0,0),(0,0),(0,0)],
  [(0,0),(0,0),(0,0),(0,0)],
  [(0,0),(0,0),(0,0),(0,0)],
  [(0,0),(0,0),(0,0),(0,0)])
R(cp_0, L104_0, [(-4,-4,15.18,26.68)])
R(cp_0, L235_5, [(0,0,11.18,22.68)])
cp_0.add(gdstk.Reference(scm_nmos_4295876_x1_y1_1, (7.31,15.12), rotation=pi, x_reflection=True))
cp_0.add(gdstk.Reference(scm_pmos_7694812_x1_y1_1, (2.58,0)))
cp_0.add(gdstk.Reference(inv_1445845_0_0_16764815, (2.58,15.12), rotation=pi))
cp_0.add(gdstk.Reference(inv_1445845_1_0_16764815, (8.6,15.12), x_reflection=True))
cp_0.add(gdstk.Reference(dp_nmos_87919044_x1_y1_1, (2.58,15.12), x_reflection=True))
cp_0.add(gdstk.Reference(dcl_nmos_s_53290777_x1_y, (9.89,15.12), rotation=pi, x_reflection=True))
cp_0.add(gdstk.Reference(dcl_pmos_s_72600235_x1_y, (1.29,15.12)))
cp_0.add(gdstk.Reference(c_pmos_s_19745913_x1_y1_16_, (8.6,7.56), rotation=pi))
cp_0.add(gdstk.Reference(c_pmos_s_19745913_x1_y1_16_, (8.6,15.12), rotation=pi))
cp_0.add(gdstk.Label('VSS', (1.72,11.34), layer=69, texttype=5))
cp_0.add(gdstk.Label('VDD', (1.72,3.78), layer=69, texttype=5))
cp_0.add(gdstk.Label('UP', (0.86,7.14), layer=68, texttype=5))
cp_0.add(gdstk.Label('DN', (10.32,7.14), layer=68, texttype=5))
cp_0.add(gdstk.Label('OUT', (7.74,7.14), layer=68, texttype=5))

lib.write_gds('CP_0.gds')
